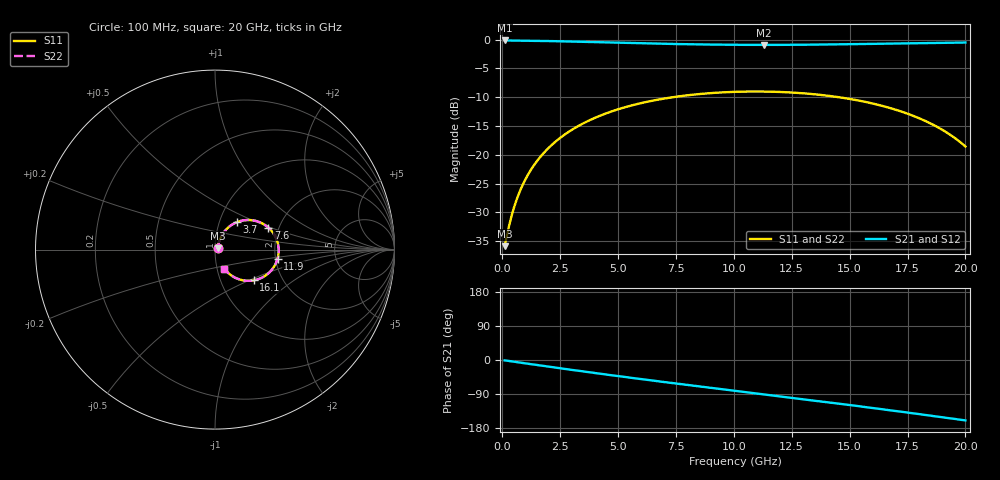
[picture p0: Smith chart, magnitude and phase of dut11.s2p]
! Touchstone file exported from HFSS 2026.1.0
!  File:  C:/ffzhzh/LocalFiles/Ansys_Project_Files/temp_test_TSV_RDL_11_1782979653_45308.aedt
!  Generated:  04:19:37 PM Jul  2, 2026
!  Design:  TSV_RDL
!  Project:  temp_test_TSV_RDL_11_1782979653_45308
! Variables:
!  h_bsmrdl = 4.42um
!  h_ox = 20um
!  h_rdl = 5um
!  h_sub = 97.16um
!  h_tmrdl = 3.52um
!  h_tsv = 97.16um
!  h_via = 3um
!  l_bsmrdl = 510.87um
!  l_sub = 2441.71um
!  l_tmrdl = 104.94um
!  m_sub = 200um
!  pitch = 27.36um
!  r_tsv = 5.58um
!  s_tmrdl = 10um
!  w_bsmrdl = 13.7um
!  w_sub = 500um
!  w_tmrdl = 16.08um
!  x_tsv_center1 = 112.98um
!  x_tsv_center2 = 637.55um
!  x_tsv_center3 = 758.57um
!  x_tsv_center4 = 1283.14um
!  x_tsv_center5 = 1404.16um
!  x_tsv_center6 = 1928.73um
# GHz S MA R 50.000000
! Terminal data exported
! Port[1] = TM_RDL1_1_T1
! Port[2] = TM_RDL5_1_T1
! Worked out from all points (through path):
!   200 points, 100 MHz to 20 GHz, reference 50 ohm
!   highest |S21| = -0.13 dB at 100 MHz (marker M1); lowest = -0.9 dB at 11.3 GHz (marker M2)
!   group delay of S21, straight-line fit = 21.7 ps
!   lowest |S11| = -35.9 dB at 100 MHz (marker M3), VSWR 1.03, Z = 51.5 + j0.651 ohm
!   |S11| at or under -10 dB: start of sweep to 7.347 GHz; 14.55 GHz to end of sweep
!   |S22| runs from -35.9 to -9.0 dB; largest |S21 - S12| = 7.7e-13
!   S11 on the Smith chart (normalised r, x): 100 MHz: 1.03, +0.01; 3.7 GHz: 1.21, +0.39; 7.6 GHz: 1.76, +0.48; 11.9 GHz: 2.05, -0.24; 16.1 GHz: 1.44, -0.53; 20 GHz: 1.08, -0.23
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0.1  0.01609 23.1  0.9853 -0.9  0.9853 -0.9  0.01609 23.1
! Gamma 0 0 0 0
! Port Impedance 50 0 50 0
0.4  0.02944 53.2  0.9836 -3.6  0.9836 -3.6  0.02944 53.2
0.6  0.03978 59.7  0.9826 -5.4  0.9826 -5.4  0.03978 59.7
0.9  0.05586 63.8  0.9811 -8.0  0.9811 -8.0  0.05586 63.8
1.3  0.07758 64.9  0.9788 -11.5  0.9788 -11.5  0.07758 64.9
1.7  0.09908 63.8  0.9759 -15.0  0.9759 -15.0  0.09908 63.9
2.2  0.1252 61.4  0.9718 -19.3  0.9718 -19.3  0.1252 61.4
3.5  0.1878 52.7  0.9587 -30.2  0.9587 -30.2  0.1878 52.7
3.7  0.1967 51.2  0.9565 -31.9  0.9565 -31.9  0.1967 51.2
5.1  0.2522 40.8  0.9409 -43.3  0.9409 -43.3  0.2521 40.8
6.8  0.3035 28.3  0.9234 -56.7  0.9234 -56.7  0.3035 28.3
7.6  0.3215 22.4  0.9166 -62.8  0.9166 -62.8  0.3215 22.4
10.1  0.3528 4.5  0.9032 -81.7  0.9032 -81.7  0.3528 4.5
11.3  0.3546 -4.0  0.9016 -90.7  0.9016 -90.7  0.3546 -4.0
11.9  0.3522 -8.3  0.902 -95.2  0.902 -95.2  0.3522 -8.3
13.4  0.337 -19.0  0.9061 -106.5  0.9061 -106.5  0.337 -19.0
14.8  0.3107 -29.0  0.9133 -117.3  0.9133 -117.3  0.3107 -29.0
16.1  0.2759 -38.3  0.9218 -127.5  0.9218 -127.5  0.2759 -38.3
16.7  0.2566 -42.7  0.9261 -132.2  0.9261 -132.2  0.2566 -42.6
18.6  0.1828 -55.9  0.9387 -147.7  0.9387 -147.7  0.1828 -55.9
19.3  0.1514 -60.3  0.9424 -153.6  0.9424 -153.6  0.1514 -60.2
20  0.1182 -63.9  0.9453 -159.4  0.9453 -159.4  0.1182 -63.9
